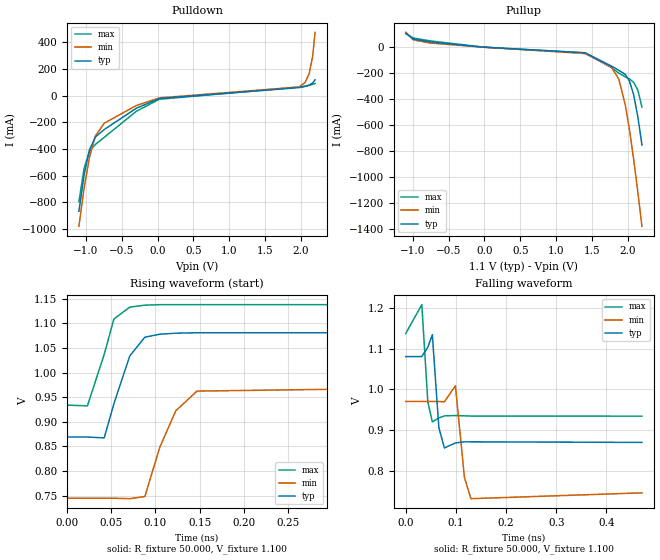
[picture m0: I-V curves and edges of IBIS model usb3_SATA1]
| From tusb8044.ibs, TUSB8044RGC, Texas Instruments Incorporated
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[Model]   usb3_SATA1
Model_type   Output
Polarity   Inverting
Vmeas = 0.96V
Vref = 1.1
Rref = 50
|   typ   min   max
|   (nom PVT)   (Fast PVT)   (slow PVT)
C_comp   0.5348pF   0.5225pF   0.5522pF
[Voltage Range]   1.1   0.99   1.155
[Temperature Range]   27   105   -40
[Pullup Reference]   1.1   0.99   1.155
[Pulldown Reference]   0   0   0
[Power Clamp Reference]   1.1   0.99   1.155
[GND Clamp Reference]   0   0   0
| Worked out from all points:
|   slope of the pulldown table from 0 to 0.165 V, typ, clamps not added: 14 ohm
|   slope of the pullup table from 0 to 0.165 V, typ, clamps not added: 40 ohm
|   falling waveform, R_fixture 50.000, V_fixture 1.100: 20-80 % time 6.91ps typ, 9.83ps min, 5.71ps max; typ from 1.08 V to 0.869 V
|   rising waveform, R_fixture 50.000, V_fixture 1.100: 20-80 % time 22.8ps typ, 27.8ps min, 20.9ps max; typ from 0.869 V to 1.08 V
[Pulldown]
|   Voltage   I(typ)   I(min)   I(max)
-1.1V     -868.9mA   -981.1mA   -796.9mA
-1.026V   -591.5mA   -690mA     -543.5mA
-951.1mV  -405.4mA   -461.1mA   -416.4mA
-868.4mV  -309.8mA   -301.2mA   -365.6mA
-744.4mV  -253.7mA   -206.5mA   -312.2mA
-297.7mV  -94.05mA   -73.91mA   -117.4mA
24.81mV   -21.49mA   -16.51mA   -26.68mA
1.977V    60.53mA    65.43mA    65.05mA
2.059V    68.81mA    98.55mA    72.03mA
2.117V    78.81mA    163.5mA    77.89mA
2.167V    95.9mA     297.7mA    84.86mA
2.2V      118.6mA    476.1mA    91.68mA
[Pullup]
|   Voltage   I(typ)   I(min)   I(max)
-1.1V     108.7mA    115.9mA    105.4mA
-992.5mV  63.95mA    57.32mA    71.65mA
-760.9mV  41.82mA    32.99mA    49.68mA
-16.54mV  1.455mA    1.316mA    1.593mA
1.406V    -41.39mA   -47.96mA   -43.61mA
1.77V     -143.3mA   -149.8mA   -155mA
1.877V    -176.7mA   -245mA     -198.4mA
1.968V    -208.9mA   -446.3mA   -227.1mA
2.026V    -260.1mA   -635.7mA   -243.8mA
2.084V    -364.9mA   -860.9mA   -269.2mA
2.142V    -532.4mA   -1.111A    -328.4mA
2.2V      -751.7mA   -1.378A    -460mA
[Ramp]
R_load = 50
|   typ   min   max
dV/dt_r   0.129193/2.27921e-11   0.134045/2.77619e-11   0.1226/2.09021e-11
dV/dt_f   0.129208/6.91542e-12   0.134061/9.83104e-12   0.122619/5.70782e-12
[Falling Waveform]
R_fixture = 50.000
V_fixture = 1.100
V_fixture_min = 0.990
V_fixture_max = 1.155
C_fixture = 0.000
|  time   V(typ)   V(min)   V(max)
0s        1.081V     970.3mV    1.138V
32ps      1.081V     970.3mV    1.209V
44ps      1.104V     970.3mV    969.3mV
53ps      1.135V     970.3mV    920mV
66ps      906mV      970.2mV    929.5mV
77ps      855.6mV    969.3mV    934.7mV
99ps      868mV      1.009V     935.6mV
117ps     870.8mV    782.9mV    934.8mV
130ps     870.7mV    730.5mV    934.3mV
471ps     869.3mV    744.9mV    934mV
[Rising Waveform]
R_fixture = 50.000
V_fixture = 1.100
V_fixture_min = 0.990
V_fixture_max = 1.155
C_fixture = 0.000
|  time   V(typ)   V(min)   V(max)
0s        869.3mV    744.9mV    934mV
23ps      869.2mV    744.9mV    932.5mV
42ps      867.5mV    744.9mV    1.037V
53ps      936.8mV    744.9mV    1.109V
71ps      1.034V     744mV      1.133V
88ps      1.072V     748.4mV    1.137V
105ps     1.078V     848.8mV    1.138V
123ps     1.08V      922.4mV    1.138V
147ps     1.081V     962.5mV    1.138V
471ps     1.081V     970.3mV    1.138V
